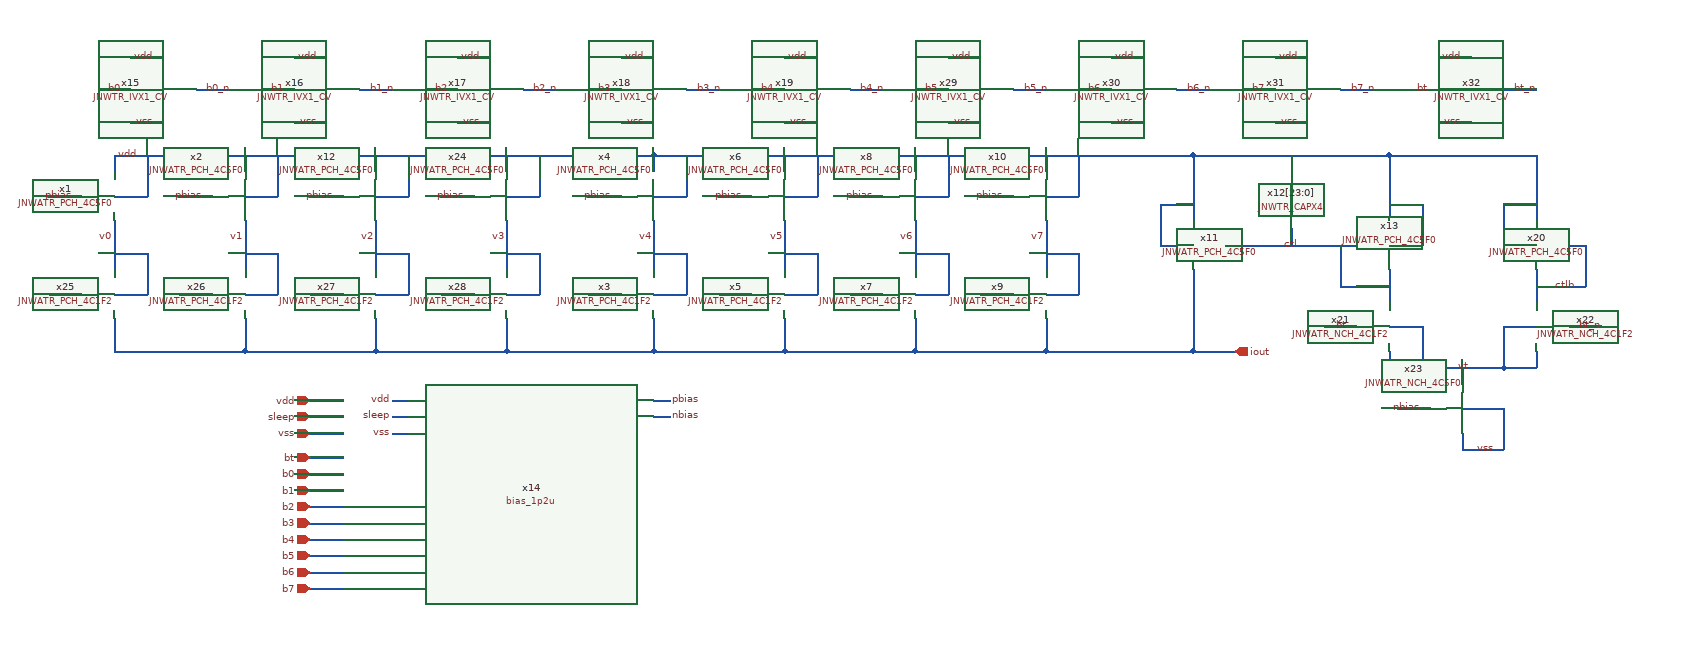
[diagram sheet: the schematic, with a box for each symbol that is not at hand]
v {xschem version=3.4.6 file_version=1.2}
G {}
K {}
V {}
S {}
E {}
N 930 290 970 290 {lab=pbias}
N 1010 240 1010 260 {lab=vdd}
N 1010 320 1010 380 {lab=v4}
N 1010 440 1010 480 {lab=iout}
N 930 410 970 410 {lab=b4_n}
N 1010 290 1050 290 {lab=vdd}
N 1050 240 1050 290 {lab=vdd}
N 1010 410 1050 410 {lab=v4}
N 1050 360 1050 410 {lab=v4}
N 1010 360 1050 360 {lab=v4}
N 1010 480 1170 480 {lab=iout}
N 1090 290 1130 290 {lab=pbias}
N 1170 240 1170 260 {lab=vdd}
N 1170 320 1170 380 {lab=v5}
N 1170 440 1170 480 {lab=iout}
N 1090 410 1130 410 {lab=b5_n}
N 1170 290 1210 290 {lab=vdd}
N 1210 240 1210 290 {lab=vdd}
N 1170 410 1210 410 {lab=v5}
N 1210 360 1210 410 {lab=v5}
N 1170 360 1210 360 {lab=v5}
N 1170 480 1330 480 {lab=iout}
N 1250 290 1290 290 {lab=pbias}
N 1330 240 1330 260 {lab=vdd}
N 1330 320 1330 380 {lab=v6}
N 1330 440 1330 480 {lab=iout}
N 1250 410 1290 410 {lab=b6_n}
N 1330 290 1370 290 {lab=vdd}
N 1370 240 1370 290 {lab=vdd}
N 1330 410 1370 410 {lab=v6}
N 1370 360 1370 410 {lab=v6}
N 1330 360 1370 360 {lab=v6}
N 1330 480 1490 480 {lab=iout}
N 1410 290 1450 290 {lab=pbias}
N 1490 240 1490 260 {lab=vdd}
N 1490 320 1490 380 {lab=v7}
N 1490 440 1490 480 {lab=iout}
N 1410 410 1450 410 {lab=b7_n}
N 1490 290 1530 290 {lab=vdd}
N 1530 240 1530 290 {lab=vdd}
N 1490 410 1530 410 {lab=v7}
N 1530 360 1530 410 {lab=v7}
N 1490 360 1530 360 {lab=v7}
N 1010 240 1670 240 {lab=vdd}
N 330 160 370 160 {lab=b0}
N 590 650 630 650 {lab=b1}
N 590 670 630 670 {lab=b2}
N 590 690 630 690 {lab=b3}
N 590 710 630 710 {lab=b4}
N 370 120 410 120 {lab=vdd}
N 370 200 410 200 {lab=vss}
N 450 160 490 160 {lab=b0_n}
N 530 160 570 160 {lab=b1}
N 570 120 610 120 {lab=vdd}
N 570 200 610 200 {lab=vss}
N 650 160 690 160 {lab=b1_n}
N 730 160 770 160 {lab=b2}
N 770 120 810 120 {lab=vdd}
N 770 200 810 200 {lab=vss}
N 850 160 890 160 {lab=b2_n}
N 930 160 970 160 {lab=b3}
N 970 120 1010 120 {lab=vdd}
N 970 200 1010 200 {lab=vss}
N 1050 160 1090 160 {lab=b3_n}
N 1130 160 1170 160 {lab=b4}
N 1170 120 1210 120 {lab=vdd}
N 1170 200 1210 200 {lab=vss}
N 1250 160 1290 160 {lab=b4_n}
N 590 630 630 630 {lab=b0}
N 690 560 710 560 {lab=sleep}
N 1010 560 1030 560 {lab=nbias}
N 1010 540 1030 540 {lab=pbias}
N 690 580 710 580 {lab=vss}
N 690 540 710 540 {lab=vdd}
N 1710 350 1870 350 {lab=ctl}
N 1670 240 1670 320 {lab=vdd}
N 1490 480 1670 480 {lab=iout}
N 1790 330 1790 350 {lab=ctl}
N 1790 240 1790 260 {lab=vdd}
N 1670 240 1910 240 {lab=vdd}
N 1910 240 1910 320 {lab=vdd}
N 1910 350 1950 350 {lab=vdd}
N 1950 300 1950 350 {lab=vdd}
N 1910 300 1950 300 {lab=vdd}
N 1850 350 1850 400 {lab=ctl}
N 1850 400 1910 400 {lab=ctl}
N 1910 380 1910 420 {lab=ctl}
N 2130 350 2150 350 {lab=ctlb}
N 2090 240 2090 320 {lab=vdd}
N 2050 350 2090 350 {lab=vdd}
N 2050 300 2050 350 {lab=vdd}
N 2150 350 2150 400 {lab=ctlb}
N 2090 400 2150 400 {lab=ctlb}
N 2090 380 2090 420 {lab=ctlb}
N 1910 240 2090 240 {lab=vdd}
N 2050 300 2090 300 {lab=vdd}
N 1670 380 1670 480 {lab=iout}
N 2050 450 2090 450 {lab=vt}
N 2050 450 2050 500 {lab=vt}
N 2050 500 2090 500 {lab=vt}
N 1910 450 1950 450 {lab=vt}
N 1950 450 1950 500 {lab=vt}
N 1910 500 1950 500 {lab=vt}
N 1910 480 1910 500 {lab=vt}
N 2090 480 2090 500 {lab=vt}
N 1830 450 1870 450 {lab=bt}
N 2130 450 2170 450 {lab=bt_n}
N 1950 500 2050 500 {lab=vt}
N 2000 500 2000 520 {lab=vt}
N 2050 550 2050 600 {lab=vss}
N 1630 350 1670 350 {lab=vdd}
N 1630 300 1630 350 {lab=vdd}
N 1630 300 1670 300 {lab=vdd}
N 2000 580 2000 600 {lab=vss}
N 2000 550 2050 550 {lab=vss}
N 2000 600 2050 600 {lab=vss}
N 1920 550 1960 550 {lab=nbias}
N 1670 480 1720 480 {lab=iout}
N 590 560 630 560 {lab=sleep}
N 590 540 630 540 {lab=vdd}
N 590 580 630 580 {lab=vss}
N 270 290 310 290 {lab=pbias}
N 350 240 350 260 {lab=vdd}
N 350 320 350 380 {lab=v0}
N 350 440 350 480 {lab=iout}
N 270 410 310 410 {lab=b0_n}
N 350 290 390 290 {lab=vdd}
N 390 240 390 290 {lab=vdd}
N 350 410 390 410 {lab=v0}
N 390 360 390 410 {lab=v0}
N 350 360 390 360 {lab=v0}
N 350 480 510 480 {lab=iout}
N 430 290 470 290 {lab=pbias}
N 510 240 510 260 {lab=vdd}
N 510 320 510 380 {lab=v1}
N 510 440 510 480 {lab=iout}
N 430 410 470 410 {lab=b1_n}
N 510 290 550 290 {lab=vdd}
N 550 240 550 290 {lab=vdd}
N 510 410 550 410 {lab=v1}
N 550 360 550 410 {lab=v1}
N 510 360 550 360 {lab=v1}
N 510 480 670 480 {lab=iout}
N 590 290 630 290 {lab=pbias}
N 670 240 670 260 {lab=vdd}
N 670 320 670 380 {lab=v2}
N 670 440 670 480 {lab=iout}
N 590 410 630 410 {lab=b2_n}
N 670 290 710 290 {lab=vdd}
N 710 240 710 290 {lab=vdd}
N 670 410 710 410 {lab=v2}
N 710 360 710 410 {lab=v2}
N 670 360 710 360 {lab=v2}
N 670 480 830 480 {lab=iout}
N 750 290 790 290 {lab=pbias}
N 830 240 830 260 {lab=vdd}
N 830 320 830 380 {lab=v3}
N 830 440 830 480 {lab=iout}
N 750 410 790 410 {lab=b3_n}
N 830 290 870 290 {lab=vdd}
N 870 240 870 290 {lab=vdd}
N 830 410 870 410 {lab=v3}
N 870 360 870 410 {lab=v3}
N 830 360 870 360 {lab=v3}
N 350 240 1010 240 {lab=vdd}
N 830 480 1010 480 {lab=iout}
N 590 730 630 730 {lab=b5}
N 590 750 630 750 {lab=b6}
N 590 770 630 770 {lab=b7}
N 1330 160 1370 160 {lab=b5}
N 1370 120 1410 120 {lab=vdd}
N 1370 200 1410 200 {lab=vss}
N 1450 160 1490 160 {lab=b5_n}
N 1530 160 1570 160 {lab=b6}
N 1570 120 1610 120 {lab=vdd}
N 1570 200 1610 200 {lab=vss}
N 1650 160 1690 160 {lab=b6_n}
N 1730 160 1770 160 {lab=b7}
N 1770 120 1810 120 {lab=vdd}
N 1770 200 1810 200 {lab=vss}
N 1850 160 1890 160 {lab=b7_n}
N 1930 160 1970 160 {lab=bt}
N 1970 120 2010 120 {lab=vdd}
N 1970 200 2010 200 {lab=vss}
N 2050 160 2090 160 {lab=bt_n}
N 590 610 630 610 {lab=bt}
C {JNW_ATR_SKY130A/JNWATR_PCH_4C5F0.sym} 970 290 0 0 {name=x4 }
C {JNW_ATR_SKY130A/JNWATR_PCH_4C5F0.sym} 1130 290 0 0 {name=x6 }
C {JNW_ATR_SKY130A/JNWATR_PCH_4C5F0.sym} 1290 290 0 0 {name=x8 }
C {JNW_ATR_SKY130A/JNWATR_PCH_4C5F0.sym} 1450 290 0 0 {name=x10 }
C {devices/lab_wire.sym} 1440 410 0 0 {name=p3 sig_type=std_logic lab=b7_n
}
C {devices/lab_wire.sym} 1280 410 0 0 {name=p4 sig_type=std_logic lab=b6_n
}
C {devices/lab_wire.sym} 1120 410 0 0 {name=p5 sig_type=std_logic lab=b5_n
}
C {devices/lab_wire.sym} 960 410 0 0 {name=p6 sig_type=std_logic lab=b4_n
}
C {devices/ipin.sym} 590 540 0 0 {name=p14 lab=vdd}
C {devices/ipin.sym} 590 580 0 0 {name=p15 lab=vss}
C {devices/ipin.sym} 590 650 0 0 {name=p17 lab=b1}
C {devices/ipin.sym} 590 670 0 0 {name=p18 lab=b2}
C {devices/ipin.sym} 590 690 0 0 {name=p19 lab=b3}
C {devices/ipin.sym} 590 710 0 0 {name=p20 lab=b4}
C {JNW_TR_SKY130A/JNWTR_IVX1_CV.sym} 370 160 0 0 {name=x15 }
C {devices/lab_wire.sym} 400 200 2 1 {name=p23 sig_type=std_logic lab=vss}
C {devices/lab_wire.sym} 400 120 0 0 {name=p24 sig_type=std_logic lab=vdd}
C {JNW_TR_SKY130A/JNWTR_IVX1_CV.sym} 570 160 0 0 {name=x16 }
C {devices/lab_wire.sym} 600 200 2 1 {name=p26 sig_type=std_logic lab=vss}
C {devices/lab_wire.sym} 600 120 0 0 {name=p27 sig_type=std_logic lab=vdd}
C {JNW_TR_SKY130A/JNWTR_IVX1_CV.sym} 770 160 0 0 {name=x17 }
C {devices/lab_wire.sym} 800 200 2 1 {name=p30 sig_type=std_logic lab=vss}
C {devices/lab_wire.sym} 800 120 0 0 {name=p31 sig_type=std_logic lab=vdd}
C {JNW_TR_SKY130A/JNWTR_IVX1_CV.sym} 970 160 0 0 {name=x18 }
C {devices/lab_wire.sym} 1000 200 2 1 {name=p34 sig_type=std_logic lab=vss}
C {devices/lab_wire.sym} 1000 120 0 0 {name=p35 sig_type=std_logic lab=vdd}
C {JNW_TR_SKY130A/JNWTR_IVX1_CV.sym} 1170 160 0 0 {name=x19 }
C {devices/lab_wire.sym} 1200 200 2 1 {name=p38 sig_type=std_logic lab=vss}
C {devices/lab_wire.sym} 1200 120 0 0 {name=p39 sig_type=std_logic lab=vdd}
C {devices/lab_wire.sym} 360 160 0 0 {name=p16 sig_type=std_logic lab=b0}
C {devices/lab_wire.sym} 960 160 0 0 {name=p25 sig_type=std_logic lab=b3}
C {devices/lab_wire.sym} 560 160 0 0 {name=p28 sig_type=std_logic lab=b1}
C {devices/lab_wire.sym} 1160 160 0 0 {name=p29 sig_type=std_logic lab=b4}
C {devices/lab_wire.sym} 760 160 0 0 {name=p32 sig_type=std_logic lab=b2}
C {devices/ipin.sym} 590 630 0 0 {name=p7 lab=b0}
C {devices/lab_wire.sym} 1060 160 0 1 {name=p36 sig_type=std_logic lab=b3_n}
C {devices/lab_wire.sym} 460 160 0 1 {name=p37 sig_type=std_logic lab=b0_n}
C {devices/lab_wire.sym} 660 160 0 1 {name=p40 sig_type=std_logic lab=b1_n}
C {devices/lab_wire.sym} 1260 160 0 1 {name=p41 sig_type=std_logic lab=b4_n}
C {devices/lab_wire.sym} 860 160 0 1 {name=p45 sig_type=std_logic lab=b2_n}
C {devices/lab_wire.sym} 1120 290 0 0 {name=p9 sig_type=std_logic lab=pbias
}
C {devices/lab_wire.sym} 1280 290 0 0 {name=p8 sig_type=std_logic lab=pbias
}
C {devices/lab_wire.sym} 1440 290 0 0 {name=p10 sig_type=std_logic lab=pbias
}
C {devices/lab_wire.sym} 960 290 0 0 {name=p12 sig_type=std_logic lab=pbias
}
C {devices/ipin.sym} 590 560 0 0 {name=p33 lab=sleep}
C {devices/lab_wire.sym} 1030 540 0 1 {name=p13 sig_type=std_logic lab=pbias
}
C {devices/lab_wire.sym} 1030 560 0 1 {name=p21 sig_type=std_logic lab=nbias
}
C {JNW_ATR_SKY130A/JNWATR_PCH_4C5F0.sym} 1710 350 0 1 {name=x11 }
C {JNW_ATR_SKY130A/JNWATR_PCH_4C1F2.sym} 970 410 0 0 {name=x3 }
C {JNW_ATR_SKY130A/JNWATR_PCH_4C1F2.sym} 1130 410 0 0 {name=x5 }
C {JNW_ATR_SKY130A/JNWATR_PCH_4C1F2.sym} 1290 410 0 0 {name=x7 }
C {JNW_ATR_SKY130A/JNWATR_PCH_4C1F2.sym} 1450 410 0 0 {name=x9 }
C {JNW_TR_SKY130A/JNWTR_CAPX4.sym} 1790 320 0 0 {name=x12[23:0]}
C {JNW_ATR_SKY130A/JNWATR_PCH_4C5F0.sym} 1870 350 0 0 {name=x13 }
C {JNW_ATR_SKY130A/JNWATR_PCH_4C5F0.sym} 2130 350 0 1 {name=x20 }
C {JNW_ATR_SKY130A/JNWATR_NCH_4C1F2.sym} 1870 450 0 0 {name=x21 }
C {JNW_ATR_SKY130A/JNWATR_NCH_4C1F2.sym} 2130 450 0 1 {name=x22 }
C {devices/lab_wire.sym} 2140 450 0 1 {name=p1 sig_type=std_logic lab=bt_n}
C {devices/lab_wire.sym} 1860 450 0 0 {name=p2 sig_type=std_logic lab=bt}
C {JNW_ATR_SKY130A/JNWATR_NCH_4C5F0.sym} 1960 550 0 0 {name=x23 }
C {devices/lab_wire.sym} 1950 550 0 0 {name=p11 sig_type=std_logic lab=nbias
}
C {devices/lab_wire.sym} 1800 350 2 1 {name=p42 sig_type=std_logic lab=ctl
}
C {devices/lab_wire.sym} 2110 400 2 0 {name=p43 sig_type=std_logic lab=ctlb
}
C {devices/lab_wire.sym} 2010 500 0 0 {name=p44 sig_type=std_logic lab=vt}
C {devices/lab_wire.sym} 1490 340 2 1 {name=p46 sig_type=std_logic lab=v7}
C {devices/lab_wire.sym} 1330 340 2 1 {name=p47 sig_type=std_logic lab=v6}
C {devices/lab_wire.sym} 1170 340 2 1 {name=p48 sig_type=std_logic lab=v5}
C {devices/lab_wire.sym} 1010 340 2 1 {name=p49 sig_type=std_logic lab=v4
}
C {devices/lab_wire.sym} 690 580 0 0 {name=p50 sig_type=std_logic lab=vss
}
C {devices/lab_wire.sym} 690 540 0 0 {name=p51 sig_type=std_logic lab=vdd
}
C {devices/opin.sym} 1720 480 0 0 {name=p54 lab=iout}
C {devices/lab_wire.sym} 2040 600 0 0 {name=p52 sig_type=std_logic lab=vss
}
C {devices/lab_wire.sym} 690 560 0 0 {name=p53 sig_type=std_logic lab=sleep
}
C {JNW_ATR_SKY130A/JNWATR_PCH_4C5F0.sym} 310 290 0 0 {name=x1 }
C {JNW_ATR_SKY130A/JNWATR_PCH_4C5F0.sym} 470 290 0 0 {name=x2 }
C {JNW_ATR_SKY130A/JNWATR_PCH_4C5F0.sym} 630 290 0 0 {name=x12 }
C {JNW_ATR_SKY130A/JNWATR_PCH_4C5F0.sym} 790 290 0 0 {name=x24 }
C {devices/lab_wire.sym} 780 410 0 0 {name=p55 sig_type=std_logic lab=b3_n
}
C {devices/lab_wire.sym} 620 410 0 0 {name=p56 sig_type=std_logic lab=b2_n
}
C {devices/lab_wire.sym} 460 410 0 0 {name=p57 sig_type=std_logic lab=b1_n
}
C {devices/lab_wire.sym} 300 410 0 0 {name=p58 sig_type=std_logic lab=b0_n
}
C {devices/lab_wire.sym} 460 290 0 0 {name=p59 sig_type=std_logic lab=pbias
}
C {devices/lab_wire.sym} 620 290 0 0 {name=p60 sig_type=std_logic lab=pbias
}
C {devices/lab_wire.sym} 780 290 0 0 {name=p61 sig_type=std_logic lab=pbias
}
C {devices/lab_wire.sym} 300 290 0 0 {name=p62 sig_type=std_logic lab=pbias
}
C {JNW_ATR_SKY130A/JNWATR_PCH_4C1F2.sym} 310 410 0 0 {name=x25 }
C {JNW_ATR_SKY130A/JNWATR_PCH_4C1F2.sym} 470 410 0 0 {name=x26 }
C {JNW_ATR_SKY130A/JNWATR_PCH_4C1F2.sym} 630 410 0 0 {name=x27 }
C {JNW_ATR_SKY130A/JNWATR_PCH_4C1F2.sym} 790 410 0 0 {name=x28 }
C {devices/lab_wire.sym} 830 340 2 1 {name=p63 sig_type=std_logic lab=v3}
C {devices/lab_wire.sym} 670 340 2 1 {name=p64 sig_type=std_logic lab=v2}
C {devices/lab_wire.sym} 510 340 2 1 {name=p65 sig_type=std_logic lab=v1}
C {devices/lab_wire.sym} 350 340 2 1 {name=p66 sig_type=std_logic lab=v0
}
C {devices/lab_wire.sym} 380 240 0 0 {name=p67 sig_type=std_logic lab=vdd
}
C {devices/ipin.sym} 590 730 0 0 {name=p22 lab=b5}
C {devices/ipin.sym} 590 750 0 0 {name=p68 lab=b6}
C {devices/ipin.sym} 590 770 0 0 {name=p69 lab=b7}
C {JNW_TR_SKY130A/JNWTR_IVX1_CV.sym} 1370 160 0 0 {name=x29 }
C {devices/lab_wire.sym} 1400 200 2 1 {name=p70 sig_type=std_logic lab=vss}
C {devices/lab_wire.sym} 1400 120 0 0 {name=p71 sig_type=std_logic lab=vdd}
C {devices/lab_wire.sym} 1360 160 0 0 {name=p72 sig_type=std_logic lab=b5}
C {devices/lab_wire.sym} 1460 160 0 1 {name=p73 sig_type=std_logic lab=b5_n}
C {JNW_TR_SKY130A/JNWTR_IVX1_CV.sym} 1570 160 0 0 {name=x30 }
C {devices/lab_wire.sym} 1600 200 2 1 {name=p74 sig_type=std_logic lab=vss}
C {devices/lab_wire.sym} 1600 120 0 0 {name=p75 sig_type=std_logic lab=vdd}
C {devices/lab_wire.sym} 1560 160 0 0 {name=p76 sig_type=std_logic lab=b6}
C {devices/lab_wire.sym} 1660 160 0 1 {name=p77 sig_type=std_logic lab=b6_n}
C {JNW_TR_SKY130A/JNWTR_IVX1_CV.sym} 1770 160 0 0 {name=x31 }
C {devices/lab_wire.sym} 1800 200 2 1 {name=p78 sig_type=std_logic lab=vss}
C {devices/lab_wire.sym} 1800 120 0 0 {name=p79 sig_type=std_logic lab=vdd}
C {devices/lab_wire.sym} 1760 160 0 0 {name=p80 sig_type=std_logic lab=b7}
C {devices/lab_wire.sym} 1860 160 0 1 {name=p81 sig_type=std_logic lab=b7_n}
C {JNW_TR_SKY130A/JNWTR_IVX1_CV.sym} 1970 160 0 0 {name=x32 }
C {devices/lab_wire.sym} 2000 200 2 1 {name=p82 sig_type=std_logic lab=vss}
C {devices/lab_wire.sym} 2000 120 0 0 {name=p83 sig_type=std_logic lab=vdd}
C {devices/lab_wire.sym} 1960 160 0 0 {name=p84 sig_type=std_logic lab=bt}
C {devices/lab_wire.sym} 2060 160 0 1 {name=p85 sig_type=std_logic lab=bt_n}
C {devices/ipin.sym} 590 610 0 0 {name=p86 lab=bt}
C {LELO_TORD_SKY130A/bias_1p2u.sym} 860 560 0 0 {name=x14}
